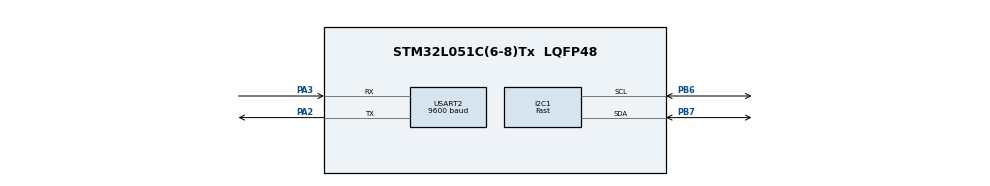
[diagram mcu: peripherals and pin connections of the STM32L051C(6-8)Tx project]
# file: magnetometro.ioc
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Mcu.Family=STM32L0
RCC.MSI_VALUE=2097000
I2C1.I2C_Speed_Mode=I2C_Fast
USART2.BaudRate=9600
ProjectManager.StackSize=0x400
PA13.Signal=SYS_SWDIO
PA3.Mode=Asynchronous
RCC.HSI16_VALUE=16000000
ProjectManager.TargetToolchain=STM32CubeIDE
RCC.APB2TimFreq_Value=2097000
PB6.Signal=I2C1_SCL
I2C1.Timing=0x00000000
PB6.Mode=I2C
I2C1.AddressingMode=I2C_ADDRESSINGMODE_10BIT
RCC.LSE_VALUE=32768
RCC.AHBFreq_Value=2097000
RCC.HSE_VALUE=8000000
board=custom
USART2.VirtualMode-Asynchronous=VM_ASYNC
RCC.VCOOutputFreq_Value=48000000
RCC.APB2Freq_Value=2097000
PA14.Mode=Serial_Wire
PB7.Signal=I2C1_SDA
PA13.Mode=Serial_Wire
Mcu.Name=STM32L051C(6-8)Tx
PA2.Signal=USART2_TX
RCC.SYSCLKFreq_VALUE=2097000
Mcu.Package=LQFP48
PB7.Mode=I2C
PA14.Signal=SYS_SWCLK
ProjectManager.HeapSize=0x200
RCC.HSI_VALUE=16000000
RCC.APB1TimFreq_Value=2097000
PA2.Mode=Asynchronous
RCC.APB1Freq_Value=2097000
PA3.Signal=USART2_RX

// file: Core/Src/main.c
/* USER CODE BEGIN Header */
/**
  ******************************************************************************
  * @file           : main.c
  * @brief          : Main program body
  ******************************************************************************
  * @attention
  *
  * <h2><center>&copy; Copyright (c) 2023 STMicroelectronics.
  * All rights reserved.</center></h2>
  *
  * This software component is licensed by ST under BSD 3-Clause license,
  * the "License"; You may not use this file except in compliance with the
  * License. You may obtain a copy of the License at:
  *                        opensource.org/licenses/BSD-3-Clause
  *
  ******************************************************************************
  */
/* USER CODE END Header */
#include "main.h"
#include "FXOS8700.h"

I2C_HandleTypeDef hi2c1;

UART_HandleTypeDef huart2;

void SystemClock_Config(void);
static void MX_GPIO_Init(void);
static void MX_I2C1_Init(void);
static void MX_USART2_UART_Init(void);
void MX_USART1_PRINTWELCOME(void);
void get_data_from_sensor(void);

void MX_USART1_PRINTWELCOME(void)
{

	  uint8_t message[35] = {'\0'};
	  sprintf(message, "Welcome to lab! Counting\r\n");
	  HAL_UART_Transmit(&huart2, message, sizeof(message), 100);
}

/* USER CODE END 0 */

void get_data_from_sensor(void)
{

	  ReadAccelMagnData(&hi2c1);

	  uint8_t message[50] = {0};

	  int16_t magX = getData(GET_MAG_X);
	  int16_t magY = getData(GET_MAG_Y);
	  int16_t magZ = getData(GET_MAG_Z);
	  sprintf(message, "\r\nMG - X: %d Y: %d Z: %d\r\n", magX, magY, magZ);
	  HAL_UART_Transmit(&huart2, message, sizeof(message), 100);
}
int main(void)
{

  /* MCU Configuration--------------------------------------------------------*/

  /* Reset of all peripherals, Initializes the Flash interface and the Systick. */
  HAL_Init();

  /* Configure the system clock */
  SystemClock_Config();

  /* Initialize all configured peripherals */
  MX_GPIO_Init();
  MX_I2C1_Init();
  MX_USART2_UART_Init();
  /* USER CODE BEGIN 2 */

  MX_USART1_PRINTWELCOME();
  /*uint8_t wiam = magnetometter_get_who_am_i(&hi2c1);
  uint8_t message[50] = {0};
  memset(message, 0, sizeof(message));
  sprintf(message, "MG - teste %02X\r\n", wiam);
  HAL_UART_Transmit(&huart2, message, sizeof(message), 100);*/

  while(magnetometter_init(&hi2c1) != HAL_OK);

  uint8_t message[50] = {0};
  memset(message, 0, sizeof(message));
  memset(message, 0, sizeof(message));
  sprintf(message, "MG - Started\r\nMG -Reading...\r\n");
  HAL_UART_Transmit(&huart2, message, sizeof(message), 100);

  /* USER CODE END 2 */

  /* Infinite loop */
  while (1)
  {
	  get_data_from_sensor();
	  HAL_Delay(500);

  }
}

void SystemClock_Config(void)
{
  /*RCC_OscInitTypeDef RCC_OscInitStruct = {0};
  RCC_ClkInitTypeDef RCC_ClkInitStruct = {0};
  RCC_PeriphCLKInitTypeDef PeriphClkInit = {0};

  /// Configure the main internal regulator output voltage

  __HAL_PWR_VOLTAGESCALING_CONFIG(PWR_REGULATOR_VOLTAGE_SCALE1);
  // Initializes the RCC Oscillators according to the specified parameters
  // in the RCC_OscInitTypeDef structure.

  RCC_OscInitStruct.OscillatorType = RCC_OSCILLATORTYPE_MSI;
  RCC_OscInitStruct.MSIState = RCC_MSI_ON;
  RCC_OscInitStruct.MSICalibrationValue = 0;
  RCC_OscInitStruct.MSIClockRange = RCC_MSIRANGE_5;
  RCC_OscInitStruct.PLL.PLLState = RCC_PLL_NONE;
  if (HAL_RCC_OscConfig(&RCC_OscInitStruct) != HAL_OK)
  {
    Error_Handler();
  }
  // Initializes the CPU, AHB and APB buses clocks

  RCC_ClkInitStruct.ClockType = RCC_CLOCKTYPE_HCLK|RCC_CLOCKTYPE_SYSCLK
                              |RCC_CLOCKTYPE_PCLK1|RCC_CLOCKTYPE_PCLK2;
  RCC_ClkInitStruct.SYSCLKSource = RCC_SYSCLKSOURCE_MSI;
  RCC_ClkInitStruct.AHBCLKDivider = RCC_SYSCLK_DIV1;
  RCC_ClkInitStruct.APB1CLKDivider = RCC_HCLK_DIV1;
  RCC_ClkInitStruct.APB2CLKDivider = RCC_HCLK_DIV1;

  if (HAL_RCC_ClockConfig(&RCC_ClkInitStruct, FLASH_LATENCY_0) != HAL_OK)
  {
    Error_Handler();
  }
  PeriphClkInit.PeriphClockSelection = RCC_PERIPHCLK_USART2|RCC_PERIPHCLK_I2C1;
  PeriphClkInit.Usart2ClockSelection = RCC_USART2CLKSOURCE_PCLK1;
  PeriphClkInit.I2c1ClockSelection = RCC_I2C1CLKSOURCE_PCLK1;
  if (HAL_RCCEx_PeriphCLKConfig(&PeriphClkInit) != HAL_OK)
  {
    Error_Handler();
  }*/

	RCC_OscInitTypeDef RCC_OscInitStruct = {0};
	  RCC_ClkInitTypeDef RCC_ClkInitStruct = {0};

	  /* Enable HSE Oscillator and Activate PLL with HSE as source */
	  RCC_OscInitStruct.OscillatorType      = RCC_OSCILLATORTYPE_HSI;
	  RCC_OscInitStruct.HSEState            = RCC_HSE_OFF;
	  RCC_OscInitStruct.HSIState            = RCC_HSI_ON;
	  RCC_OscInitStruct.HSICalibrationValue = RCC_HSICALIBRATION_DEFAULT;
	  RCC_OscInitStruct.PLL.PLLState        = RCC_PLL_ON;//RCC_PLL_OFF;//RCC_PLL_ON;
	  RCC_OscInitStruct.PLL.PLLSource       = RCC_PLLSOURCE_HSI;
	  RCC_OscInitStruct.PLL.PLLMUL          = RCC_PLLMUL_6;//RCC_PLLMUL_3;//RCC_PLLMUL_6;
	  RCC_OscInitStruct.PLL.PLLDIV          = RCC_PLLDIV_3;

	  if (HAL_RCC_OscConfig(&RCC_OscInitStruct) != HAL_OK)
	  {
	    Error_Handler();
	  }

	  /* Set Voltage scale1 as MCU will run at 32MHz */
	  __HAL_RCC_PWR_CLK_ENABLE();
	  __HAL_PWR_VOLTAGESCALING_CONFIG(PWR_REGULATOR_VOLTAGE_SCALE1);

	  /* Poll VOSF bit of in PWR_CSR. Wait until it is reset to 0 */
	  while (__HAL_PWR_GET_FLAG(PWR_FLAG_VOS) != RESET) {};

	  /* Select PLL as system clock source and configure the HCLK, PCLK1 and PCLK2
	  clocks dividers */
	  RCC_ClkInitStruct.ClockType = (RCC_CLOCKTYPE_SYSCLK | RCC_CLOCKTYPE_HCLK | RCC_CLOCKTYPE_PCLK1 | RCC_CLOCKTYPE_PCLK2);
	  RCC_ClkInitStruct.SYSCLKSource = RCC_SYSCLKSOURCE_PLLCLK;//RCC_SYSCLKSOURCE_HSI;//RCC_SYSCLKSOURCE_PLLCLK;
	  RCC_ClkInitStruct.AHBCLKDivider = RCC_SYSCLK_DIV1;
	  RCC_ClkInitStruct.APB1CLKDivider = RCC_HCLK_DIV16;
	  RCC_ClkInitStruct.APB2CLKDivider = RCC_HCLK_DIV1;
	  if (HAL_RCC_ClockConfig(&RCC_ClkInitStruct, FLASH_LATENCY_1) != HAL_OK)
	  {
	    Error_Handler();
	  }
}

static void MX_I2C1_Init(void)
{

	  hi2c1.Instance = I2C1;
	  hi2c1.Init.Timing = 0x10909CEC;//0x00303D5B; // Timing configurado para operação a 400 kHz em Fast Mode
	  hi2c1.Init.OwnAddress1 = 0;
	  hi2c1.Init.AddressingMode = I2C_ADDRESSINGMODE_7BIT;
	  hi2c1.Init.DualAddressMode = I2C_DUALADDRESS_DISABLE;
	  hi2c1.Init.OwnAddress2 = 0;
	  hi2c1.Init.GeneralCallMode = I2C_GENERALCALL_DISABLE;
	  hi2c1.Init.NoStretchMode = I2C_NOSTRETCH_DISABLE;

	  if (HAL_I2C_Init(&hi2c1) != HAL_OK)
	  {
	    Error_Handler(); // Tratamento de erro
	  }

}

static void MX_USART2_UART_Init(void)
{

  huart2.Instance = USART2;
  huart2.Init.BaudRate = 9600;
  huart2.Init.WordLength = UART_WORDLENGTH_8B;
  huart2.Init.StopBits = UART_STOPBITS_1;
  huart2.Init.Parity = UART_PARITY_NONE;
  huart2.Init.Mode = UART_MODE_TX_RX;
  huart2.Init.HwFlowCtl = UART_HWCONTROL_NONE;
  huart2.Init.OverSampling = UART_OVERSAMPLING_16;
  huart2.Init.OneBitSampling = UART_ONE_BIT_SAMPLE_DISABLE;
  huart2.AdvancedInit.AdvFeatureInit = UART_ADVFEATURE_NO_INIT;
  if (HAL_UART_Init(&huart2) != HAL_OK)
  {
    Error_Handler();
  }

}

static void MX_GPIO_Init(void)
{

  /* GPIO Ports Clock Enable */
  __HAL_RCC_GPIOA_CLK_ENABLE();
  __HAL_RCC_GPIOB_CLK_ENABLE();

}

void Error_Handler(void)
{
  __disable_irq();
  while (1)
  {
  }
}

/************************ (C) COPYRIGHT STMicroelectronics *****END OF FILE****/
